VERSION 5.7 ;
BUSBITCHARS "[]" ;
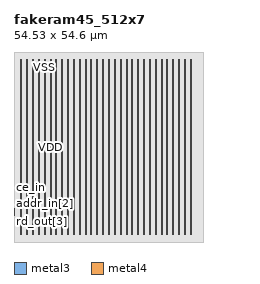
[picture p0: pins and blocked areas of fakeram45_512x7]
MACRO fakeram45_512x7
  FOREIGN fakeram45_512x7 0 0 ;
  SYMMETRY X Y R90 ;
  SIZE 54.530 BY 54.600 ;
  CLASS BLOCK ;
  PIN w_mask_in[0]
    DIRECTION INPUT ;
    USE SIGNAL ;
    SHAPE ABUTMENT ;
    PORT
      LAYER metal3 ;
      RECT 0.000 2.135 0.070 2.205 ;
    END
  END w_mask_in[0]
  PIN w_mask_in[1]
    DIRECTION INPUT ;
    USE SIGNAL ;
    SHAPE ABUTMENT ;
    PORT
      LAYER metal3 ;
      RECT 0.000 2.415 0.070 2.485 ;
    END
  END w_mask_in[1]
  PIN w_mask_in[2]
    DIRECTION INPUT ;
    USE SIGNAL ;
    SHAPE ABUTMENT ;
    PORT
      LAYER metal3 ;
      RECT 0.000 2.695 0.070 2.765 ;
    END
  END w_mask_in[2]
  PIN w_mask_in[3]
    DIRECTION INPUT ;
    USE SIGNAL ;
    SHAPE ABUTMENT ;
    PORT
      LAYER metal3 ;
      RECT 0.000 2.975 0.070 3.045 ;
    END
  END w_mask_in[3]
  PIN w_mask_in[4]
    DIRECTION INPUT ;
    USE SIGNAL ;
    SHAPE ABUTMENT ;
    PORT
      LAYER metal3 ;
      RECT 0.000 3.255 0.070 3.325 ;
    END
  END w_mask_in[4]
  PIN w_mask_in[5]
    DIRECTION INPUT ;
    USE SIGNAL ;
    SHAPE ABUTMENT ;
    PORT
      LAYER metal3 ;
      RECT 0.000 3.535 0.070 3.605 ;
    END
  END w_mask_in[5]
  PIN w_mask_in[6]
    DIRECTION INPUT ;
    USE SIGNAL ;
    SHAPE ABUTMENT ;
    PORT
      LAYER metal3 ;
      RECT 0.000 3.815 0.070 3.885 ;
    END
  END w_mask_in[6]
  PIN rd_out[0]
    DIRECTION OUTPUT ;
    USE SIGNAL ;
    SHAPE ABUTMENT ;
    PORT
      LAYER metal3 ;
      RECT 0.000 4.935 0.070 5.005 ;
    END
  END rd_out[0]
  PIN rd_out[1]
    DIRECTION OUTPUT ;
    USE SIGNAL ;
    SHAPE ABUTMENT ;
    PORT
      LAYER metal3 ;
      RECT 0.000 5.215 0.070 5.285 ;
    END
  END rd_out[1]
  PIN rd_out[2]
    DIRECTION OUTPUT ;
    USE SIGNAL ;
    SHAPE ABUTMENT ;
    PORT
      LAYER metal3 ;
      RECT 0.000 5.495 0.070 5.565 ;
    END
  END rd_out[2]
  PIN rd_out[3]
    DIRECTION OUTPUT ;
    USE SIGNAL ;
    SHAPE ABUTMENT ;
    PORT
      LAYER metal3 ;
      RECT 0.000 5.775 0.070 5.845 ;
    END
  END rd_out[3]
  PIN rd_out[4]
    DIRECTION OUTPUT ;
    USE SIGNAL ;
    SHAPE ABUTMENT ;
    PORT
      LAYER metal3 ;
      RECT 0.000 6.055 0.070 6.125 ;
    END
  END rd_out[4]
  PIN rd_out[5]
    DIRECTION OUTPUT ;
    USE SIGNAL ;
    SHAPE ABUTMENT ;
    PORT
      LAYER metal3 ;
      RECT 0.000 6.335 0.070 6.405 ;
    END
  END rd_out[5]
  PIN rd_out[6]
    DIRECTION OUTPUT ;
    USE SIGNAL ;
    SHAPE ABUTMENT ;
    PORT
      LAYER metal3 ;
      RECT 0.000 6.615 0.070 6.685 ;
    END
  END rd_out[6]
  PIN wd_in[0]
    DIRECTION INPUT ;
    USE SIGNAL ;
    SHAPE ABUTMENT ;
    PORT
      LAYER metal3 ;
      RECT 0.000 7.735 0.070 7.805 ;
    END
  END wd_in[0]
  PIN wd_in[1]
    DIRECTION INPUT ;
    USE SIGNAL ;
    SHAPE ABUTMENT ;
    PORT
      LAYER metal3 ;
      RECT 0.000 8.015 0.070 8.085 ;
    END
  END wd_in[1]
  PIN wd_in[2]
    DIRECTION INPUT ;
    USE SIGNAL ;
    SHAPE ABUTMENT ;
    PORT
      LAYER metal3 ;
      RECT 0.000 8.295 0.070 8.365 ;
    END
  END wd_in[2]
  PIN wd_in[3]
    DIRECTION INPUT ;
    USE SIGNAL ;
    SHAPE ABUTMENT ;
    PORT
      LAYER metal3 ;
      RECT 0.000 8.575 0.070 8.645 ;
    END
  END wd_in[3]
  PIN wd_in[4]
    DIRECTION INPUT ;
    USE SIGNAL ;
    SHAPE ABUTMENT ;
    PORT
      LAYER metal3 ;
      RECT 0.000 8.855 0.070 8.925 ;
    END
  END wd_in[4]
  PIN wd_in[5]
    DIRECTION INPUT ;
    USE SIGNAL ;
    SHAPE ABUTMENT ;
    PORT
      LAYER metal3 ;
      RECT 0.000 9.135 0.070 9.205 ;
    END
  END wd_in[5]
  PIN wd_in[6]
    DIRECTION INPUT ;
    USE SIGNAL ;
    SHAPE ABUTMENT ;
    PORT
      LAYER metal3 ;
      RECT 0.000 9.415 0.070 9.485 ;
    END
  END wd_in[6]
  PIN addr_in[0]
    DIRECTION INPUT ;
    USE SIGNAL ;
    SHAPE ABUTMENT ;
    PORT
      LAYER metal3 ;
      RECT 0.000 10.535 0.070 10.605 ;
    END
  END addr_in[0]
  PIN addr_in[1]
    DIRECTION INPUT ;
    USE SIGNAL ;
    SHAPE ABUTMENT ;
    PORT
      LAYER metal3 ;
      RECT 0.000 10.815 0.070 10.885 ;
    END
  END addr_in[1]
  PIN addr_in[2]
    DIRECTION INPUT ;
    USE SIGNAL ;
    SHAPE ABUTMENT ;
    PORT
      LAYER metal3 ;
      RECT 0.000 11.095 0.070 11.165 ;
    END
  END addr_in[2]
  PIN addr_in[3]
    DIRECTION INPUT ;
    USE SIGNAL ;
    SHAPE ABUTMENT ;
    PORT
      LAYER metal3 ;
      RECT 0.000 11.375 0.070 11.445 ;
    END
  END addr_in[3]
  PIN addr_in[4]
    DIRECTION INPUT ;
    USE SIGNAL ;
    SHAPE ABUTMENT ;
    PORT
      LAYER metal3 ;
      RECT 0.000 11.655 0.070 11.725 ;
    END
  END addr_in[4]
  PIN addr_in[5]
    DIRECTION INPUT ;
    USE SIGNAL ;
    SHAPE ABUTMENT ;
    PORT
      LAYER metal3 ;
      RECT 0.000 11.935 0.070 12.005 ;
    END
  END addr_in[5]
  PIN addr_in[6]
    DIRECTION INPUT ;
    USE SIGNAL ;
    SHAPE ABUTMENT ;
    PORT
      LAYER metal3 ;
      RECT 0.000 12.215 0.070 12.285 ;
    END
  END addr_in[6]
  PIN addr_in[7]
    DIRECTION INPUT ;
    USE SIGNAL ;
    SHAPE ABUTMENT ;
    PORT
      LAYER metal3 ;
      RECT 0.000 12.495 0.070 12.565 ;
    END
  END addr_in[7]
  PIN addr_in[8]
    DIRECTION INPUT ;
    USE SIGNAL ;
    SHAPE ABUTMENT ;
    PORT
      LAYER metal3 ;
      RECT 0.000 12.775 0.070 12.845 ;
    END
  END addr_in[8]
  PIN we_in
    DIRECTION INPUT ;
    USE SIGNAL ;
    SHAPE ABUTMENT ;
    PORT
      LAYER metal3 ;
      RECT 0.000 13.055 0.070 13.125 ;
    END
  END we_in
  PIN ce_in
    DIRECTION INPUT ;
    USE SIGNAL ;
    SHAPE ABUTMENT ;
    PORT
      LAYER metal3 ;
      RECT 0.000 13.335 0.070 13.405 ;
    END
  END ce_in
  PIN clk
    DIRECTION INPUT ;
    USE SIGNAL ;
    SHAPE ABUTMENT ;
    PORT
      LAYER metal3 ;
      RECT 0.000 13.615 0.070 13.685 ;
    END
  END clk
  PIN VSS
    DIRECTION INOUT ;
    USE GROUND ;
    PORT
      LAYER metal4 ;
      RECT 1.960 2.100 2.240 52.500 ;
      RECT 5.320 2.100 5.600 52.500 ;
      RECT 8.680 2.100 8.960 52.500 ;
      RECT 12.040 2.100 12.320 52.500 ;
      RECT 15.400 2.100 15.680 52.500 ;
      RECT 18.760 2.100 19.040 52.500 ;
      RECT 22.120 2.100 22.400 52.500 ;
      RECT 25.480 2.100 25.760 52.500 ;
      RECT 28.840 2.100 29.120 52.500 ;
      RECT 32.200 2.100 32.480 52.500 ;
      RECT 35.560 2.100 35.840 52.500 ;
      RECT 38.920 2.100 39.200 52.500 ;
      RECT 42.280 2.100 42.560 52.500 ;
      RECT 45.640 2.100 45.920 52.500 ;
      RECT 49.000 2.100 49.280 52.500 ;
    END
  END VSS
  PIN VDD
    DIRECTION INOUT ;
    USE POWER ;
    PORT
      LAYER metal4 ;
      RECT 3.640 2.100 3.920 52.500 ;
      RECT 7.000 2.100 7.280 52.500 ;
      RECT 10.360 2.100 10.640 52.500 ;
      RECT 13.720 2.100 14.000 52.500 ;
      RECT 17.080 2.100 17.360 52.500 ;
      RECT 20.440 2.100 20.720 52.500 ;
      RECT 23.800 2.100 24.080 52.500 ;
      RECT 27.160 2.100 27.440 52.500 ;
      RECT 30.520 2.100 30.800 52.500 ;
      RECT 33.880 2.100 34.160 52.500 ;
      RECT 37.240 2.100 37.520 52.500 ;
      RECT 40.600 2.100 40.880 52.500 ;
      RECT 43.960 2.100 44.240 52.500 ;
      RECT 47.320 2.100 47.600 52.500 ;
      RECT 50.680 2.100 50.960 52.500 ;
    END
  END VDD
  OBS
    LAYER metal1 ;
    RECT 0 0 54.530 54.600 ;
    LAYER metal2 ;
    RECT 0 0 54.530 54.600 ;
    LAYER metal3 ;
    RECT 0.070 0 54.530 54.600 ;
    RECT 0 0.000 0.070 2.070 ;
    RECT 0 2.270 0.070 2.350 ;
    RECT 0 2.550 0.070 2.630 ;
    RECT 0 2.830 0.070 2.910 ;
    RECT 0 3.110 0.070 3.190 ;
    RECT 0 3.390 0.070 3.470 ;
    RECT 0 3.670 0.070 3.750 ;
    RECT 0 3.950 0.070 4.870 ;
    RECT 0 5.070 0.070 5.150 ;
    RECT 0 5.350 0.070 5.430 ;
    RECT 0 5.630 0.070 5.710 ;
    RECT 0 5.910 0.070 5.990 ;
    RECT 0 6.190 0.070 6.270 ;
    RECT 0 6.470 0.070 6.550 ;
    RECT 0 6.750 0.070 7.670 ;
    RECT 0 7.870 0.070 7.950 ;
    RECT 0 8.150 0.070 8.230 ;
    RECT 0 8.430 0.070 8.510 ;
    RECT 0 8.710 0.070 8.790 ;
    RECT 0 8.990 0.070 9.070 ;
    RECT 0 9.270 0.070 9.350 ;
    RECT 0 9.550 0.070 10.470 ;
    RECT 0 10.670 0.070 10.750 ;
    RECT 0 10.950 0.070 11.030 ;
    RECT 0 11.230 0.070 11.310 ;
    RECT 0 11.510 0.070 11.590 ;
    RECT 0 11.790 0.070 11.870 ;
    RECT 0 12.070 0.070 12.150 ;
    RECT 0 12.350 0.070 12.430 ;
    RECT 0 12.630 0.070 12.710 ;
    RECT 0 12.910 0.070 12.990 ;
    RECT 0 13.190 0.070 13.270 ;
    RECT 0 13.470 0.070 13.550 ;
    RECT 0 13.750 0.070 54.600 ;
    LAYER metal4 ;
    RECT 0 0 54.530 2.100 ;
    RECT 0 52.500 54.530 54.600 ;
    RECT 0.000 2.100 1.960 52.500 ;
    RECT 2.240 2.100 3.640 52.500 ;
    RECT 3.920 2.100 5.320 52.500 ;
    RECT 5.600 2.100 7.000 52.500 ;
    RECT 7.280 2.100 8.680 52.500 ;
    RECT 8.960 2.100 10.360 52.500 ;
    RECT 10.640 2.100 12.040 52.500 ;
    RECT 12.320 2.100 13.720 52.500 ;
    RECT 14.000 2.100 15.400 52.500 ;
    RECT 15.680 2.100 17.080 52.500 ;
    RECT 17.360 2.100 18.760 52.500 ;
    RECT 19.040 2.100 20.440 52.500 ;
    RECT 20.720 2.100 22.120 52.500 ;
    RECT 22.400 2.100 23.800 52.500 ;
    RECT 24.080 2.100 25.480 52.500 ;
    RECT 25.760 2.100 27.160 52.500 ;
    RECT 27.440 2.100 28.840 52.500 ;
    RECT 29.120 2.100 30.520 52.500 ;
    RECT 30.800 2.100 32.200 52.500 ;
    RECT 32.480 2.100 33.880 52.500 ;
    RECT 34.160 2.100 35.560 52.500 ;
    RECT 35.840 2.100 37.240 52.500 ;
    RECT 37.520 2.100 38.920 52.500 ;
    RECT 39.200 2.100 40.600 52.500 ;
    RECT 40.880 2.100 42.280 52.500 ;
    RECT 42.560 2.100 43.960 52.500 ;
    RECT 44.240 2.100 45.640 52.500 ;
    RECT 45.920 2.100 47.320 52.500 ;
    RECT 47.600 2.100 49.000 52.500 ;
    RECT 49.280 2.100 50.680 52.500 ;
    RECT 50.960 2.100 54.530 52.500 ;
    LAYER OVERLAP ;
    RECT 0 0 54.530 54.600 ;
  END
END fakeram45_512x7

END LIBRARY
